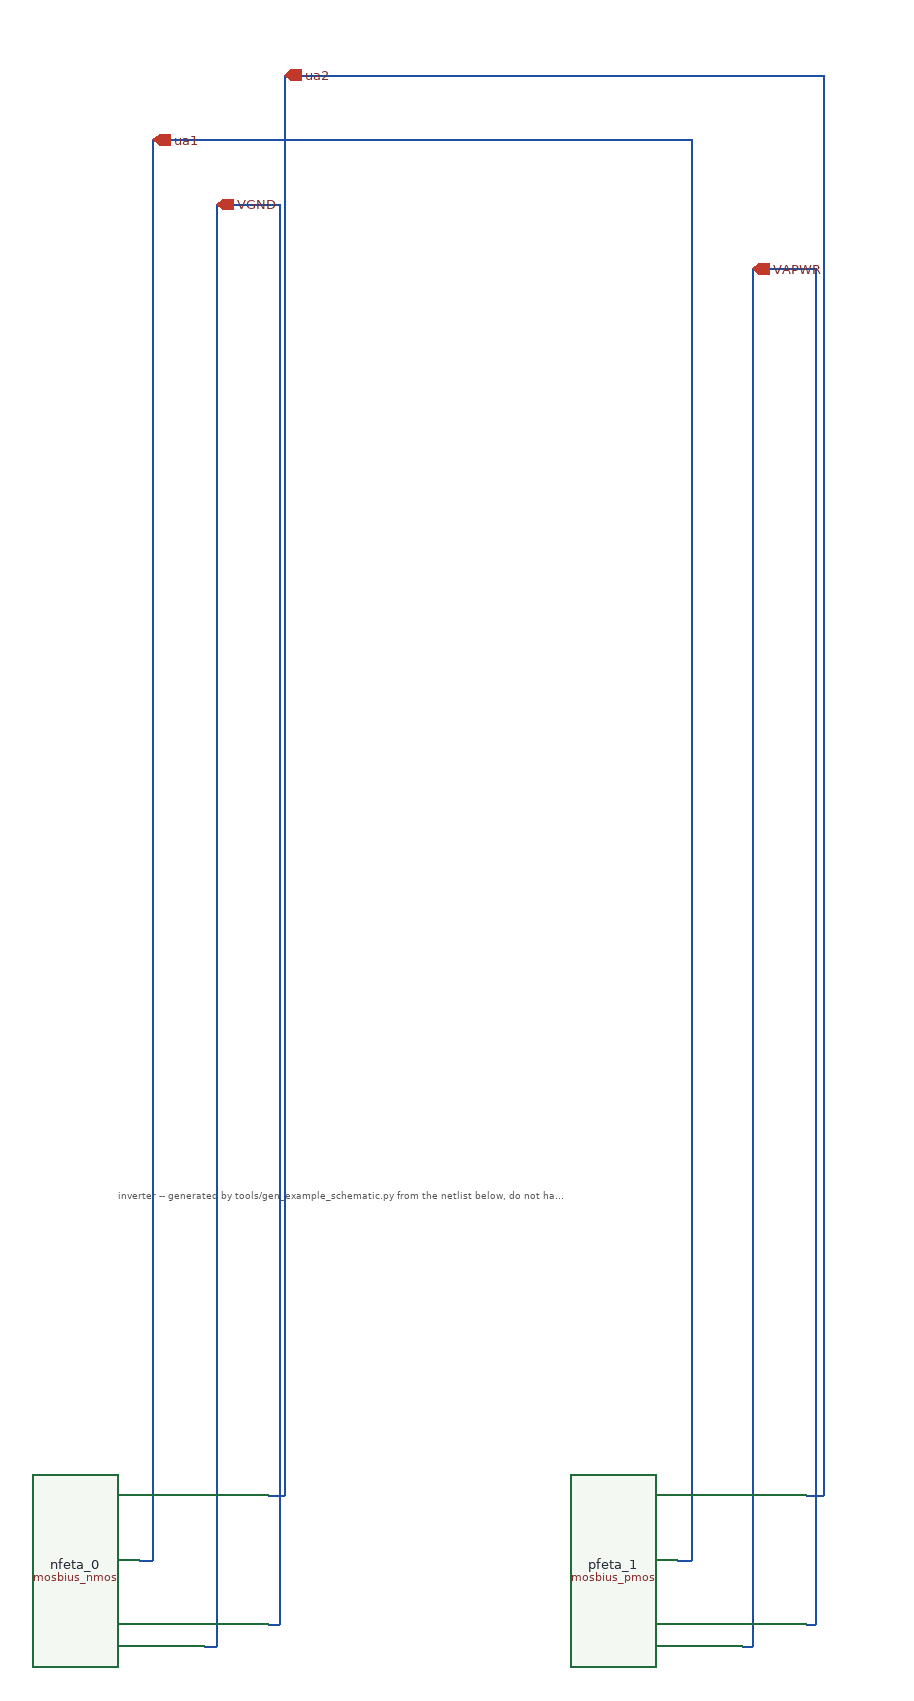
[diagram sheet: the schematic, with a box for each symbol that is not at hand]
v {xschem version=3.4.8RC file_version=1.2}
G {}
K {}
V {}
S {}
E {}
T {inverter -- generated by tools/gen_example_schematic.py from the netlist below, do not hand-edit} -80 -350 0 0 0.25 0.25 {}
N -60 0 -48 0 {
lab=ua1}
N -48 0 -48 -1320 {
lab=ua1}
N 60 -60 74 -60 {
lab=ua2}
N 74 -60 74 -1380 {
lab=ua2}
N 60 60 70 60 {
lab=VGND}
N 70 60 70 -1260 {
lab=VGND}
N 0 80 11 80 {
lab=VGND}
N 11 80 11 -1260 {
lab=VGND}
N 440 0 453 0 {
lab=ua1}
N 453 0 453 -1320 {
lab=ua1}
N 560 -60 575 -60 {
lab=ua2}
N 575 -60 575 -1380 {
lab=ua2}
N 560 60 568 60 {
lab=VAPWR}
N 568 60 568 -1200 {
lab=VAPWR}
N 500 80 509 80 {
lab=VAPWR}
N 509 80 509 -1200 {
lab=VAPWR}
N -48 -1320 453 -1320 {
lab=ua1}
C {devices/iopin.sym} -48 -1320 0 1 {name=port_ua1 lab=ua1}
N 74 -1380 575 -1380 {
lab=ua2}
C {devices/iopin.sym} 74 -1380 0 1 {name=port_ua2 lab=ua2}
N 11 -1260 70 -1260 {
lab=VGND}
C {devices/iopin.sym} 11 -1260 0 1 {name=port_VGND lab=VGND}
N 509 -1200 568 -1200 {
lab=VAPWR}
C {devices/iopin.sym} 509 -1200 0 1 {name=port_VAPWR lab=VAPWR}
C {mosbius_nmos.sym} 0 0 0 0 {name=nfeta_0 w=1}
C {mosbius_pmos.sym} 500 0 0 0 {name=pfeta_1 w=1}
